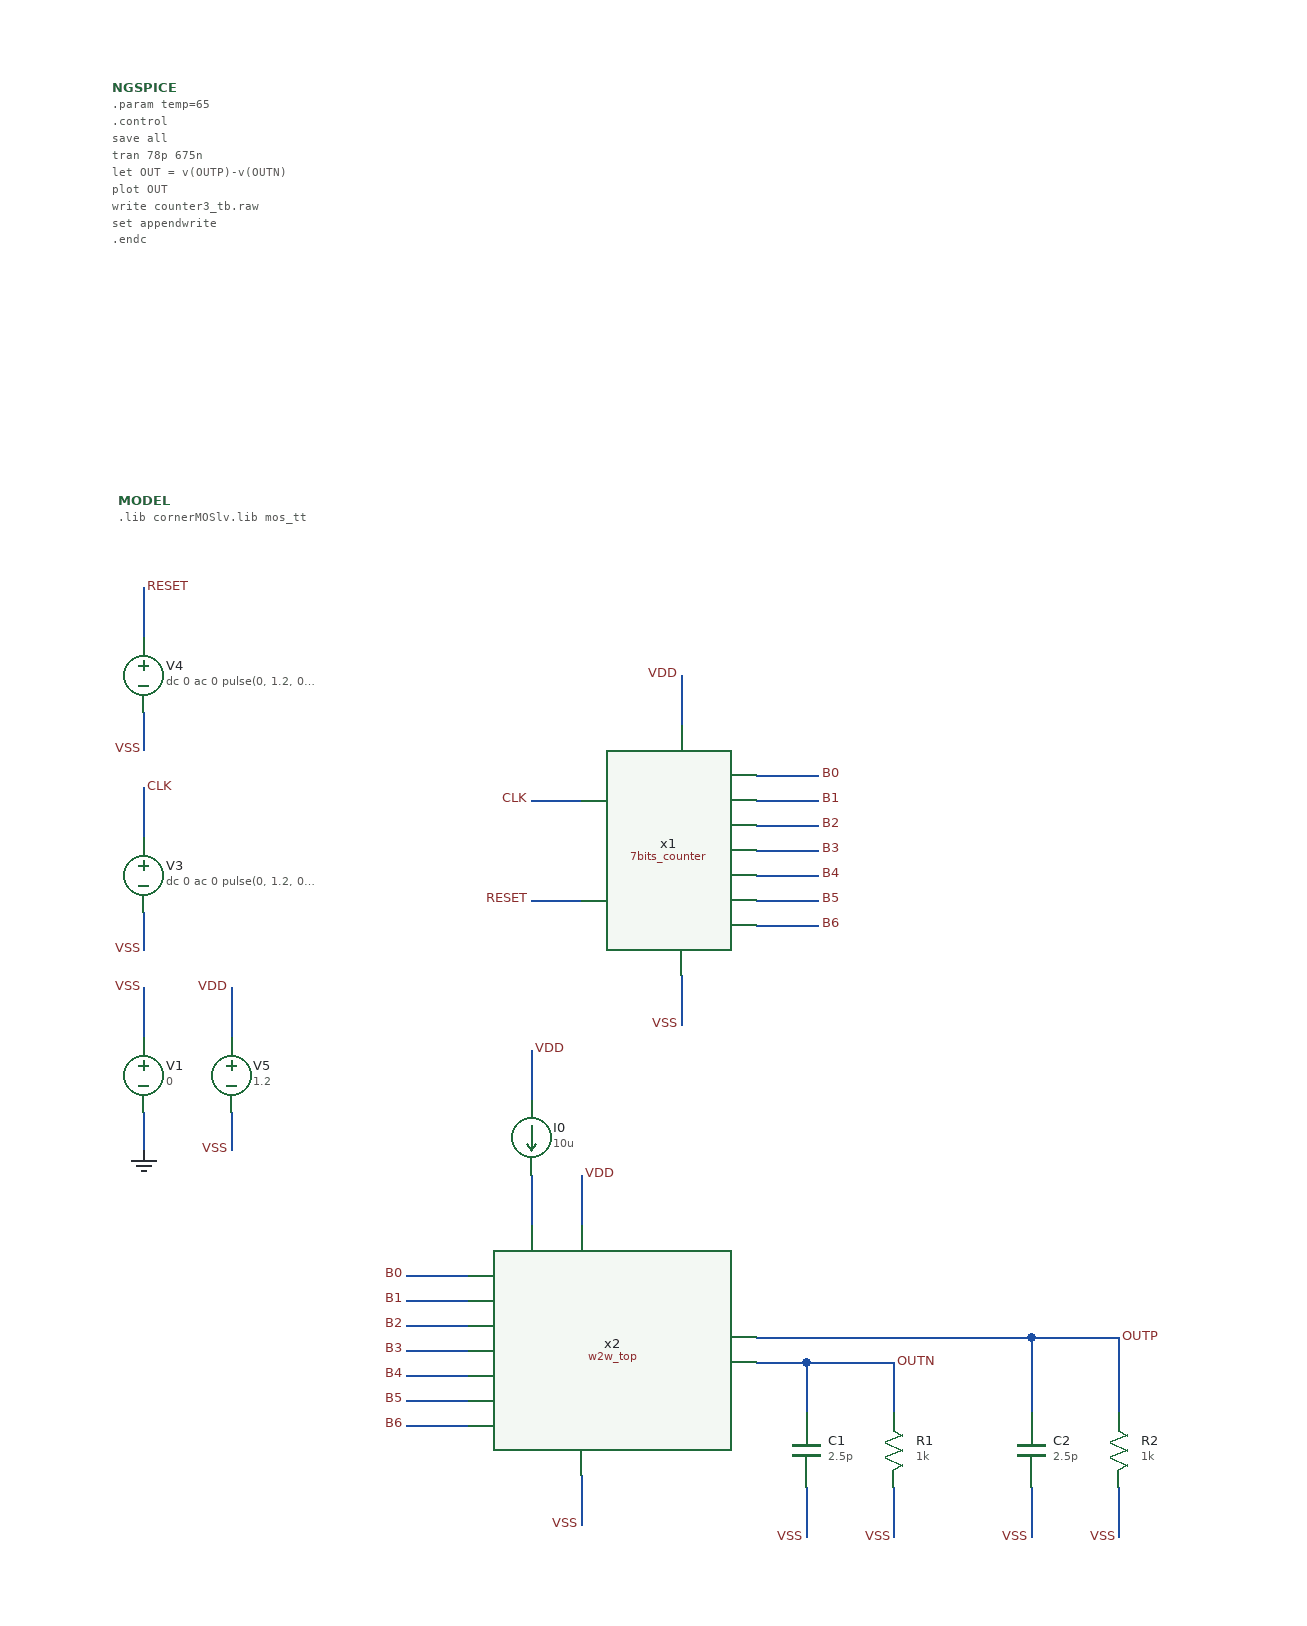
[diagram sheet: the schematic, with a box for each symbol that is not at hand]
v {xschem version=3.4.6 file_version=1.2}
G {}
K {}
V {}
S {}
E {}
B 2 1070 -530 1870 -130 {flags=graph
y1=-0.4
y2=1.5
ypos1=0
ypos2=2
divy=5
subdivy=1
unity=1
x1=0
x2=6.75e-07
divx=5
subdivx=1


dataset=-1
unitx=1
logx=0
logy=0
hilight_wave=0
color=7
node=B0}
B 2 1070 -950 1870 -550 {flags=graph
y1=-0.4
y2=1.5
ypos1=0
ypos2=2
divy=5
subdivy=1
unity=1
x1=0
x2=6.75e-07
divx=5
subdivx=1


dataset=-1
unitx=1
logx=0
logy=0
hilight_wave=0
color=21
node=CLK}
B 2 1900 -950 2700 -550 {flags=graph
y1=-0.4
y2=1.5
ypos1=0
ypos2=2
divy=5
subdivy=1
unity=1
x1=0
x2=6.75e-07
divx=5
subdivx=1


dataset=-1
unitx=1
logx=0
logy=0
hilight_wave=0
color=6
node=RESET}
B 2 1900 -530 2700 -130 {flags=graph
y2=1.5
ypos1=0
ypos2=2
divy=5
subdivy=1
unity=1
x1=0
x2=6.75e-07
divx=5
subdivx=1


dataset=-1
unitx=1
logx=0
logy=0
hilight_wave=0
color=8
node=B1
y1=-0.4}
B 2 1070 -110 1870 290 {flags=graph
y1=-0.4
y2=1.5
ypos1=0
ypos2=2
divy=5
subdivy=1
unity=1
x1=0
x2=6.75e-07
divx=5
subdivx=1


dataset=-1
unitx=1
logx=0
logy=0
hilight_wave=0
color=9
node=B2}
B 2 1900 -110 2700 290 {flags=graph
y2=1.5
ypos1=0
ypos2=2
divy=5
subdivy=1
unity=1
x1=0
x2=6.75e-07
divx=5
subdivx=1


dataset=-1
unitx=1
logx=0
logy=0
hilight_wave=0


y1=-0.4
color=10
node=B3}
B 2 1070 310 1870 710 {flags=graph
y1=-0.4
y2=1.5
ypos1=0
ypos2=2
divy=5
subdivy=1
unity=1
x1=0
x2=6.75e-07
divx=5
subdivx=1


dataset=-1
unitx=1
logx=0
logy=0
hilight_wave=0


color=12
node=B5}
B 2 1900 310 2700 710 {flags=graph
y2=1.5
ypos1=0
ypos2=2
divy=5
subdivy=1
unity=1
x1=0
x2=6.75e-07
divx=5
subdivx=1


dataset=-1
unitx=1
logx=0
logy=0
hilight_wave=0


y1=-0.4
color=13
node=B6}
B 2 230 310 1030 710 {flags=graph
y2=1.5
ypos1=0
ypos2=2
divy=5
subdivy=1
unity=1
x1=0
x2=6.75e-07
divx=5
subdivx=1


dataset=-1
unitx=1
logx=0
logy=0
hilight_wave=0


y1=-0.4
color=11
node=B4}
B 2 2720 -950 3520 -550 {flags=graph
y1=-0.00064
y2=0.019
ypos1=0
ypos2=2
divy=5
subdivy=1
unity=1
x1=0
x2=6.75e-07
divx=5
subdivx=1


dataset=-1
unitx=1
logx=0
logy=0
hilight_wave=0

color=4
node=OUTN}
B 2 2720 -530 3520 -130 {flags=graph
y2=0.019
ypos1=0
ypos2=2
divy=5
subdivy=1
unity=1
x1=0
x2=6.75e-07
divx=5
subdivx=1


dataset=-1
unitx=1
logx=0
logy=0
hilight_wave=0


y1=-0.00012
color=5
node=OUTP}
N 90 -130 90 -100 {lab=GND}
N 90 -230 90 -190 {lab=VSS}
N 90 -290 90 -260 {lab=VSS}
N 90 -450 90 -420 {lab=VSS}
N 90 -390 90 -350 {lab=CLK}
N 90 -550 90 -510 {lab=RESET}
N 160 -130 160 -100 {lab=VSS}
N 160 -230 160 -190 {lab=VDD}
N 400 -380 440 -380 {lab=CLK}
N 400 -300 440 -300 {lab=RESET}
N 520 -480 520 -440 {lab=VDD}
N 520 -240 520 -200 {lab=VSS}
N 580 -400 630 -400 {lab=B0}
N 580 -380 630 -380 {lab=B1}
N 580 -360 630 -360 {lab=B2}
N 580 -340 630 -340 {lab=B3}
N 580 -320 630 -320 {lab=B4}
N 580 -300 630 -300 {lab=B5}
N 580 -280 630 -280 {lab=B6}
N 440 160 440 200 {lab=VSS}
N 300 0 350 0 {lab=B0}
N 300 20 350 20 {lab=B1}
N 300 40 350 40 {lab=B2}
N 300 60 350 60 {lab=B3}
N 300 80 350 80 {lab=B4}
N 300 100 350 100 {lab=B5}
N 300 120 350 120 {lab=B6}
N 440 -80 440 -40 {lab=VDD}
N 400 -180 400 -140 {lab=VDD}
N 400 -80 400 -40 {lab=#net1}
N 690 70 690 110 {lab=OUTN}
N 870 50 870 110 {lab=OUTP}
N 690 170 690 210 {lab=VSS}
N 870 170 870 210 {lab=VSS}
N 620 170 620 210 {lab=VSS}
N 620 70 620 110 {lab=OUTN}
N 580 70 620 70 {lab=OUTN}
N 620 70 690 70 {lab=OUTN}
N 800 50 870 50 {lab=OUTP}
N 800 170 800 210 {lab=VSS}
N 800 50 800 110 {lab=OUTP}
N 580 50 800 50 {lab=OUTP}
C {vsource.sym} 90 -160 0 0 {name=V1 value=0 savecurrent=false}
C {vsource.sym} 90 -320 0 0 {name=V3 value="dc 0 ac 0 pulse(0, 1.2, 0, 500p, 500p, 2.5n, 5n)" savecurrent=false}
C {gnd.sym} 90 -100 0 0 {name=l1 lab=GND}
C {lab_wire.sym} 90 -230 0 0 {name=p1 sig_type=std_logic lab=VSS}
C {lab_wire.sym} 90 -260 0 0 {name=p4 sig_type=std_logic lab=VSS}
C {lab_wire.sym} 90 -420 0 0 {name=p5 sig_type=std_logic lab=VSS}
C {lab_wire.sym} 90 -390 0 1 {name=p7 sig_type=std_logic lab=CLK
}
C {lab_wire.sym} 90 -550 0 1 {name=p8 sig_type=std_logic lab=RESET
}
C {vsource.sym} 160 -160 0 0 {name=V5 value=1.2 savecurrent=false}
C {lab_wire.sym} 160 -100 0 0 {name=p12 sig_type=std_logic lab=VSS}
C {lab_wire.sym} 160 -230 0 0 {name=p13 sig_type=std_logic lab=VDD}
C {vsource.sym} 90 -480 0 0 {name=V4 value="dc 0 ac 0 pulse(0, 1.2, 0, 1p, 1p, 1n, 0)" savecurrent=false}
C {devices/code_shown.sym} 65 -950 0 0 {name=NGSPICE only_toplevel=true 
value="
.param temp=65
.control
save all 
tran 78p 675n

let OUT = v(OUTP)-v(OUTN)

plot OUT

write counter3_tb.raw
set appendwrite
.endc
"}
C {devices/launcher.sym} 505 -635 0 0 {name=h5
descr="load waves Ctrl + left click" 
tclcommand="xschem raw_read $netlist_dir/counter3_tb.raw tran"
}
C {devices/launcher.sym} 505 -705 0 0 {name=h1
descr="simulate" 
tclcommand="xschem save; xschem netlist; xschem simulate"
}
C {devices/code_shown.sym} 70 -620 0 0 {name=MODEL only_toplevel=true
format="tcleval( @value )"
value="
.lib cornerMOSlv.lib mos_tt
"}
C {lab_wire.sym} 400 -380 0 0 {name=p6 sig_type=std_logic lab=CLK
}
C {lab_wire.sym} 400 -300 0 0 {name=p16 sig_type=std_logic lab=RESET
}
C {lab_wire.sym} 520 -480 0 0 {name=p17 sig_type=std_logic lab=VDD}
C {lab_wire.sym} 520 -200 0 0 {name=p21 sig_type=std_logic lab=VSS}
C {lab_wire.sym} 630 -400 0 1 {name=p2 sig_type=std_logic lab=B0
}
C {lab_wire.sym} 630 -380 0 1 {name=p3 sig_type=std_logic lab=B1
}
C {lab_wire.sym} 630 -360 0 1 {name=p9 sig_type=std_logic lab=B2
}
C {lab_wire.sym} 630 -340 0 1 {name=p10 sig_type=std_logic lab=B3
}
C {lab_wire.sym} 630 -320 0 1 {name=p11 sig_type=std_logic lab=B4
}
C {lab_wire.sym} 630 -300 0 1 {name=p14 sig_type=std_logic lab=B5
}
C {7bits_counter.sym} 410 -220 0 0 {name=x1}
C {lab_wire.sym} 630 -280 0 1 {name=p15 sig_type=std_logic lab=B6
}
C {w2w_top.sym} 500 60 0 0 {name=x2}
C {lab_wire.sym} 440 200 0 0 {name=p18 sig_type=std_logic lab=VSS}
C {lab_wire.sym} 300 0 0 0 {name=p19 sig_type=std_logic lab=B0
}
C {lab_wire.sym} 300 20 0 0 {name=p20 sig_type=std_logic lab=B1
}
C {lab_wire.sym} 300 40 0 0 {name=p22 sig_type=std_logic lab=B2
}
C {lab_wire.sym} 300 60 0 0 {name=p23 sig_type=std_logic lab=B3
}
C {lab_wire.sym} 300 80 0 0 {name=p24 sig_type=std_logic lab=B4
}
C {lab_wire.sym} 300 100 0 0 {name=p25 sig_type=std_logic lab=B5
}
C {lab_wire.sym} 300 120 0 0 {name=p26 sig_type=std_logic lab=B6
}
C {lab_wire.sym} 440 -80 0 1 {name=p27 sig_type=std_logic lab=VDD}
C {isource.sym} 400 -110 0 0 {name=I0 value=10u}
C {lab_wire.sym} 400 -180 0 1 {name=p28 sig_type=std_logic lab=VDD}
C {res.sym} 690 140 0 0 {name=R1
value=1k
footprint=1206
device=resistor
m=1}
C {res.sym} 870 140 0 0 {name=R2
value=1k
footprint=1206
device=resistor
m=1}
C {lab_wire.sym} 690 210 0 0 {name=p29 sig_type=std_logic lab=VSS}
C {lab_wire.sym} 870 210 0 0 {name=p30 sig_type=std_logic lab=VSS}
C {lab_wire.sym} 690 70 0 1 {name=p31 sig_type=std_logic lab=OUTN}
C {lab_wire.sym} 870 50 0 1 {name=p32 sig_type=std_logic lab=OUTP}
C {capa.sym} 620 140 0 0 {name=C1
m=1
value=2.5p
footprint=1206
device="ceramic capacitor"}
C {lab_wire.sym} 620 210 0 0 {name=p33 sig_type=std_logic lab=VSS}
C {capa.sym} 800 140 0 0 {name=C2
m=1
value=2.5p
footprint=1206
device="ceramic capacitor"}
C {lab_wire.sym} 800 210 0 0 {name=p34 sig_type=std_logic lab=VSS}
